VERSION 5.7 ;
  NOWIREEXTENSIONATPIN ON ;
  DIVIDERCHAR "/" ;
  BUSBITCHARS "[]" ;
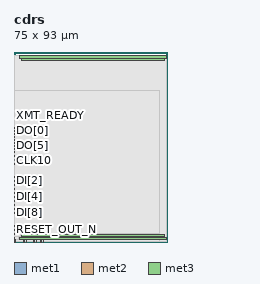
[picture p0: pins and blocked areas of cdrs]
MACRO cdrs
  CLASS BLOCK ;
  FOREIGN cdrs ;
  ORIGIN 0.000 0.000 ;
  SIZE 75.000 BY 93.000 ;
  PIN CLK10
    DIRECTION OUTPUT ;
    USE SIGNAL ;
    ANTENNAGATEAREA 0.654000 ;
    ANTENNADIFFAREA 0.445500 ;
    PORT
      LAYER met1 ;
        RECT 0.050 35.800 0.250 36.200 ;
    END
  END CLK10
  PIN CLKI
    DIRECTION INPUT ;
    USE SIGNAL ;
    ANTENNAGATEAREA 1.704000 ;
    PORT
      LAYER met2 ;
        RECT 12.970 0.000 13.270 1.000 ;
    END
  END CLKI
  PIN CLKI_N
    DIRECTION INPUT ;
    USE SIGNAL ;
    ANTENNAGATEAREA 0.852000 ;
    PORT
      LAYER met2 ;
        RECT 14.270 0.000 14.570 1.000 ;
    END
  END CLKI_N
  PIN CLKQ
    DIRECTION INPUT ;
    USE SIGNAL ;
    ANTENNAGATEAREA 1.704000 ;
    PORT
      LAYER met2 ;
        RECT 9.550 0.000 9.850 1.000 ;
    END
  END CLKQ
  PIN CLKQ_N
    DIRECTION INPUT ;
    USE SIGNAL ;
    ANTENNAGATEAREA 0.852000 ;
    PORT
      LAYER met2 ;
        RECT 10.850 0.000 11.150 1.000 ;
    END
  END CLKQ_N
  PIN DIN
    DIRECTION INPUT ;
    USE SIGNAL ;
    ANTENNAGATEAREA 0.213000 ;
    PORT
      LAYER met1 ;
        RECT 0.050 1.800 0.250 2.200 ;
    END
  END DIN
  PIN DI[0]
    DIRECTION OUTPUT ;
    USE SIGNAL ;
    ANTENNAGATEAREA 0.247500 ;
    ANTENNADIFFAREA 0.445500 ;
    PORT
      LAYER met1 ;
        RECT 0.050 33.800 0.250 34.200 ;
    END
  END DI[0]
  PIN DI[1]
    DIRECTION OUTPUT ;
    USE SIGNAL ;
    ANTENNAGATEAREA 0.247500 ;
    ANTENNADIFFAREA 0.445500 ;
    PORT
      LAYER met1 ;
        RECT 0.050 31.800 0.250 32.200 ;
    END
  END DI[1]
  PIN DI[2]
    DIRECTION OUTPUT ;
    USE SIGNAL ;
    ANTENNAGATEAREA 0.247500 ;
    ANTENNADIFFAREA 0.445500 ;
    PORT
      LAYER met1 ;
        RECT 0.050 29.800 0.250 30.200 ;
    END
  END DI[2]
  PIN DI[3]
    DIRECTION OUTPUT ;
    USE SIGNAL ;
    ANTENNAGATEAREA 0.247500 ;
    ANTENNADIFFAREA 0.445500 ;
    PORT
      LAYER met1 ;
        RECT 0.050 27.800 0.250 28.200 ;
    END
  END DI[3]
  PIN DI[4]
    DIRECTION OUTPUT ;
    USE SIGNAL ;
    ANTENNAGATEAREA 0.247500 ;
    ANTENNADIFFAREA 0.445500 ;
    PORT
      LAYER met1 ;
        RECT 0.050 25.800 0.250 26.200 ;
    END
  END DI[4]
  PIN DI[5]
    DIRECTION OUTPUT ;
    USE SIGNAL ;
    ANTENNAGATEAREA 0.247500 ;
    ANTENNADIFFAREA 0.445500 ;
    PORT
      LAYER met1 ;
        RECT 0.050 23.800 0.250 24.200 ;
    END
  END DI[5]
  PIN DI[6]
    DIRECTION OUTPUT ;
    USE SIGNAL ;
    ANTENNAGATEAREA 0.247500 ;
    ANTENNADIFFAREA 0.445500 ;
    PORT
      LAYER met1 ;
        RECT 0.050 21.800 0.250 22.200 ;
    END
  END DI[6]
  PIN DI[7]
    DIRECTION OUTPUT ;
    USE SIGNAL ;
    ANTENNAGATEAREA 0.247500 ;
    ANTENNADIFFAREA 0.445500 ;
    PORT
      LAYER met1 ;
        RECT 0.050 19.800 0.250 20.200 ;
    END
  END DI[7]
  PIN DI[8]
    DIRECTION OUTPUT ;
    USE SIGNAL ;
    ANTENNAGATEAREA 0.247500 ;
    ANTENNADIFFAREA 0.445500 ;
    PORT
      LAYER met1 ;
        RECT 0.050 17.800 0.250 18.200 ;
    END
  END DI[8]
  PIN DI[9]
    DIRECTION OUTPUT ;
    USE SIGNAL ;
    ANTENNAGATEAREA 0.247500 ;
    ANTENNADIFFAREA 0.445500 ;
    PORT
      LAYER met1 ;
        RECT 0.050 15.800 0.250 16.200 ;
    END
  END DI[9]
  PIN DOUT
    DIRECTION OUTPUT ;
    USE SIGNAL ;
    ANTENNADIFFAREA 0.796500 ;
    PORT
      LAYER met1 ;
        RECT 0.050 37.800 0.250 38.200 ;
    END
  END DOUT
  PIN DOWN_N
    DIRECTION OUTPUT ;
    USE SIGNAL ;
    ANTENNADIFFAREA 0.922000 ;
    PORT
      LAYER met2 ;
        RECT 6.025 0.000 6.325 1.000 ;
    END
  END DOWN_N
  PIN DO[0]
    DIRECTION INPUT ;
    USE SIGNAL ;
    ANTENNAGATEAREA 0.213000 ;
    PORT
      LAYER met1 ;
        RECT 0.050 54.300 0.250 54.700 ;
    END
  END DO[0]
  PIN DO[1]
    DIRECTION INPUT ;
    USE SIGNAL ;
    ANTENNAGATEAREA 0.213000 ;
    PORT
      LAYER met1 ;
        RECT 0.050 52.800 0.250 53.200 ;
    END
  END DO[1]
  PIN DO[2]
    DIRECTION INPUT ;
    USE SIGNAL ;
    ANTENNAGATEAREA 0.213000 ;
    PORT
      LAYER met1 ;
        RECT 0.050 51.300 0.250 51.700 ;
    END
  END DO[2]
  PIN DO[3]
    DIRECTION INPUT ;
    USE SIGNAL ;
    ANTENNAGATEAREA 0.213000 ;
    PORT
      LAYER met1 ;
        RECT 0.050 49.800 0.250 50.200 ;
    END
  END DO[3]
  PIN DO[4]
    DIRECTION INPUT ;
    USE SIGNAL ;
    ANTENNAGATEAREA 0.213000 ;
    PORT
      LAYER met1 ;
        RECT 0.050 48.300 0.250 48.700 ;
    END
  END DO[4]
  PIN DO[5]
    DIRECTION INPUT ;
    USE SIGNAL ;
    ANTENNAGATEAREA 0.213000 ;
    PORT
      LAYER met1 ;
        RECT 0.050 46.800 0.250 47.200 ;
    END
  END DO[5]
  PIN DO[6]
    DIRECTION INPUT ;
    USE SIGNAL ;
    ANTENNAGATEAREA 0.213000 ;
    PORT
      LAYER met1 ;
        RECT 0.050 45.300 0.250 45.700 ;
    END
  END DO[6]
  PIN DO[7]
    DIRECTION INPUT ;
    USE SIGNAL ;
    ANTENNAGATEAREA 0.213000 ;
    PORT
      LAYER met1 ;
        RECT 0.050 43.800 0.250 44.200 ;
    END
  END DO[7]
  PIN DO[8]
    DIRECTION INPUT ;
    USE SIGNAL ;
    ANTENNAGATEAREA 0.213000 ;
    PORT
      LAYER met1 ;
        RECT 0.050 41.800 0.250 42.200 ;
    END
  END DO[8]
  PIN DO[9]
    DIRECTION INPUT ;
    USE SIGNAL ;
    ANTENNAGATEAREA 0.213000 ;
    PORT
      LAYER met1 ;
        RECT 0.050 39.800 0.250 40.200 ;
    END
  END DO[9]
  PIN RESET
    DIRECTION OUTPUT ;
    USE SIGNAL ;
    ANTENNAGATEAREA 1.237500 ;
    ANTENNADIFFAREA 0.445500 ;
    PORT
      LAYER met2 ;
        RECT 0.390 0.000 0.690 1.000 ;
    END
  END RESET
  PIN RESET_N
    DIRECTION INPUT ;
    USE SIGNAL ;
    ANTENNAGATEAREA 0.213000 ;
    PORT
      LAYER met1 ;
        RECT 0.050 7.800 0.250 8.200 ;
    END
  END RESET_N
  PIN RESET_OUT_N
    DIRECTION OUTPUT ;
    USE SIGNAL ;
    ANTENNAGATEAREA 0.247500 ;
    ANTENNADIFFAREA 0.445500 ;
    PORT
      LAYER met1 ;
        RECT 0.050 9.800 0.250 10.200 ;
    END
  END RESET_OUT_N
  PIN RESTART
    DIRECTION INPUT ;
    USE SIGNAL ;
    ANTENNAGATEAREA 0.213000 ;
    PORT
      LAYER met1 ;
        RECT 0.050 5.800 0.250 6.200 ;
    END
  END RESTART
  PIN REV
    DIRECTION INPUT ;
    USE SIGNAL ;
    ANTENNAGATEAREA 0.213000 ;
    PORT
      LAYER met1 ;
        RECT 0.050 3.800 0.250 4.200 ;
    END
  END REV
  PIN SYNCED
    DIRECTION OUTPUT ;
    USE SIGNAL ;
    ANTENNAGATEAREA 1.980000 ;
    ANTENNADIFFAREA 0.445500 ;
    PORT
      LAYER met1 ;
        RECT 0.050 13.800 0.250 14.200 ;
    END
  END SYNCED
  PIN SYNCING
    DIRECTION OUTPUT ;
    USE SIGNAL ;
    ANTENNAGATEAREA 0.990000 ;
    ANTENNADIFFAREA 0.445500 ;
    PORT
      LAYER met1 ;
        RECT 0.050 11.800 0.250 12.200 ;
    END
  END SYNCING
  PIN UP_N
    DIRECTION OUTPUT ;
    USE SIGNAL ;
    ANTENNADIFFAREA 0.445500 ;
    PORT
      LAYER met2 ;
        RECT 4.720 0.000 5.020 1.000 ;
    END
  END UP_N
  PIN VGND
    DIRECTION INOUT ;
    USE GROUND ;
    PORT
      LAYER met3 ;
        RECT 2.460 1.420 74.820 2.420 ;
    END
    PORT
      LAYER met3 ;
        RECT 2.460 90.060 74.820 91.060 ;
    END
  END VGND
  PIN VPWR
    DIRECTION INOUT ;
    USE POWER ;
    PORT
      LAYER met3 ;
        RECT 3.760 2.720 73.520 3.720 ;
    END
    PORT
      LAYER met3 ;
        RECT 3.760 88.760 73.520 89.760 ;
    END
  END VPWR
  PIN XMT_RD
    DIRECTION INPUT ;
    USE SIGNAL ;
    ANTENNAGATEAREA 0.213000 ;
    PORT
      LAYER met1 ;
        RECT 0.050 55.800 0.250 56.200 ;
    END
  END XMT_RD
  PIN XMT_READY
    DIRECTION INPUT ;
    USE SIGNAL ;
    ANTENNAGATEAREA 0.213000 ;
    PORT
      LAYER met1 ;
        RECT 0.050 57.800 0.250 58.200 ;
    END
  END XMT_READY
  OBS
      LAYER nwell ;
        RECT 2.570 2.635 74.710 89.845 ;
      LAYER li1 ;
        RECT 2.760 2.635 74.520 89.845 ;
      LAYER met1 ;
        RECT 0.070 58.480 74.820 90.000 ;
        RECT 0.530 57.520 74.820 58.480 ;
        RECT 0.070 56.480 74.820 57.520 ;
        RECT 0.530 55.520 74.820 56.480 ;
        RECT 0.070 54.980 74.820 55.520 ;
        RECT 0.530 54.020 74.820 54.980 ;
        RECT 0.070 53.480 74.820 54.020 ;
        RECT 0.530 52.520 74.820 53.480 ;
        RECT 0.070 51.980 74.820 52.520 ;
        RECT 0.530 51.020 74.820 51.980 ;
        RECT 0.070 50.480 74.820 51.020 ;
        RECT 0.530 49.520 74.820 50.480 ;
        RECT 0.070 48.980 74.820 49.520 ;
        RECT 0.530 48.020 74.820 48.980 ;
        RECT 0.070 47.480 74.820 48.020 ;
        RECT 0.530 46.520 74.820 47.480 ;
        RECT 0.070 45.980 74.820 46.520 ;
        RECT 0.530 45.020 74.820 45.980 ;
        RECT 0.070 44.480 74.820 45.020 ;
        RECT 0.530 43.520 74.820 44.480 ;
        RECT 0.070 42.480 74.820 43.520 ;
        RECT 0.530 41.520 74.820 42.480 ;
        RECT 0.070 40.480 74.820 41.520 ;
        RECT 0.530 39.520 74.820 40.480 ;
        RECT 0.070 38.480 74.820 39.520 ;
        RECT 0.530 37.520 74.820 38.480 ;
        RECT 0.070 36.480 74.820 37.520 ;
        RECT 0.530 35.520 74.820 36.480 ;
        RECT 0.070 34.480 74.820 35.520 ;
        RECT 0.530 33.520 74.820 34.480 ;
        RECT 0.070 32.480 74.820 33.520 ;
        RECT 0.530 31.520 74.820 32.480 ;
        RECT 0.070 30.480 74.820 31.520 ;
        RECT 0.530 29.520 74.820 30.480 ;
        RECT 0.070 28.480 74.820 29.520 ;
        RECT 0.530 27.520 74.820 28.480 ;
        RECT 0.070 26.480 74.820 27.520 ;
        RECT 0.530 25.520 74.820 26.480 ;
        RECT 0.070 24.480 74.820 25.520 ;
        RECT 0.530 23.520 74.820 24.480 ;
        RECT 0.070 22.480 74.820 23.520 ;
        RECT 0.530 21.520 74.820 22.480 ;
        RECT 0.070 20.480 74.820 21.520 ;
        RECT 0.530 19.520 74.820 20.480 ;
        RECT 0.070 18.480 74.820 19.520 ;
        RECT 0.530 17.520 74.820 18.480 ;
        RECT 0.070 16.480 74.820 17.520 ;
        RECT 0.530 15.520 74.820 16.480 ;
        RECT 0.070 14.480 74.820 15.520 ;
        RECT 0.530 13.520 74.820 14.480 ;
        RECT 0.070 12.480 74.820 13.520 ;
        RECT 0.530 11.520 74.820 12.480 ;
        RECT 0.070 10.480 74.820 11.520 ;
        RECT 0.530 9.520 74.820 10.480 ;
        RECT 0.070 8.480 74.820 9.520 ;
        RECT 0.530 7.520 74.820 8.480 ;
        RECT 0.070 6.480 74.820 7.520 ;
        RECT 0.530 5.520 74.820 6.480 ;
        RECT 0.070 4.480 74.820 5.520 ;
        RECT 0.530 3.520 74.820 4.480 ;
        RECT 0.070 2.480 74.820 3.520 ;
        RECT 0.530 1.520 74.820 2.480 ;
        RECT 0.070 0.040 74.820 1.520 ;
      LAYER met2 ;
        RECT 0.090 1.280 74.820 91.060 ;
        RECT 0.090 0.010 0.110 1.280 ;
        RECT 0.970 0.010 4.440 1.280 ;
        RECT 5.300 0.010 5.745 1.280 ;
        RECT 6.605 0.010 9.270 1.280 ;
        RECT 10.130 0.010 10.570 1.280 ;
        RECT 11.430 0.010 12.690 1.280 ;
        RECT 13.550 0.010 13.990 1.280 ;
        RECT 14.850 0.010 74.820 1.280 ;
      LAYER met3 ;
        RECT 0.065 4.120 71.235 73.945 ;
        RECT 0.065 2.820 3.360 4.120 ;
        RECT 0.065 1.020 2.060 2.820 ;
        RECT 0.065 0.175 71.235 1.020 ;
  END
END cdrs
END LIBRARY

